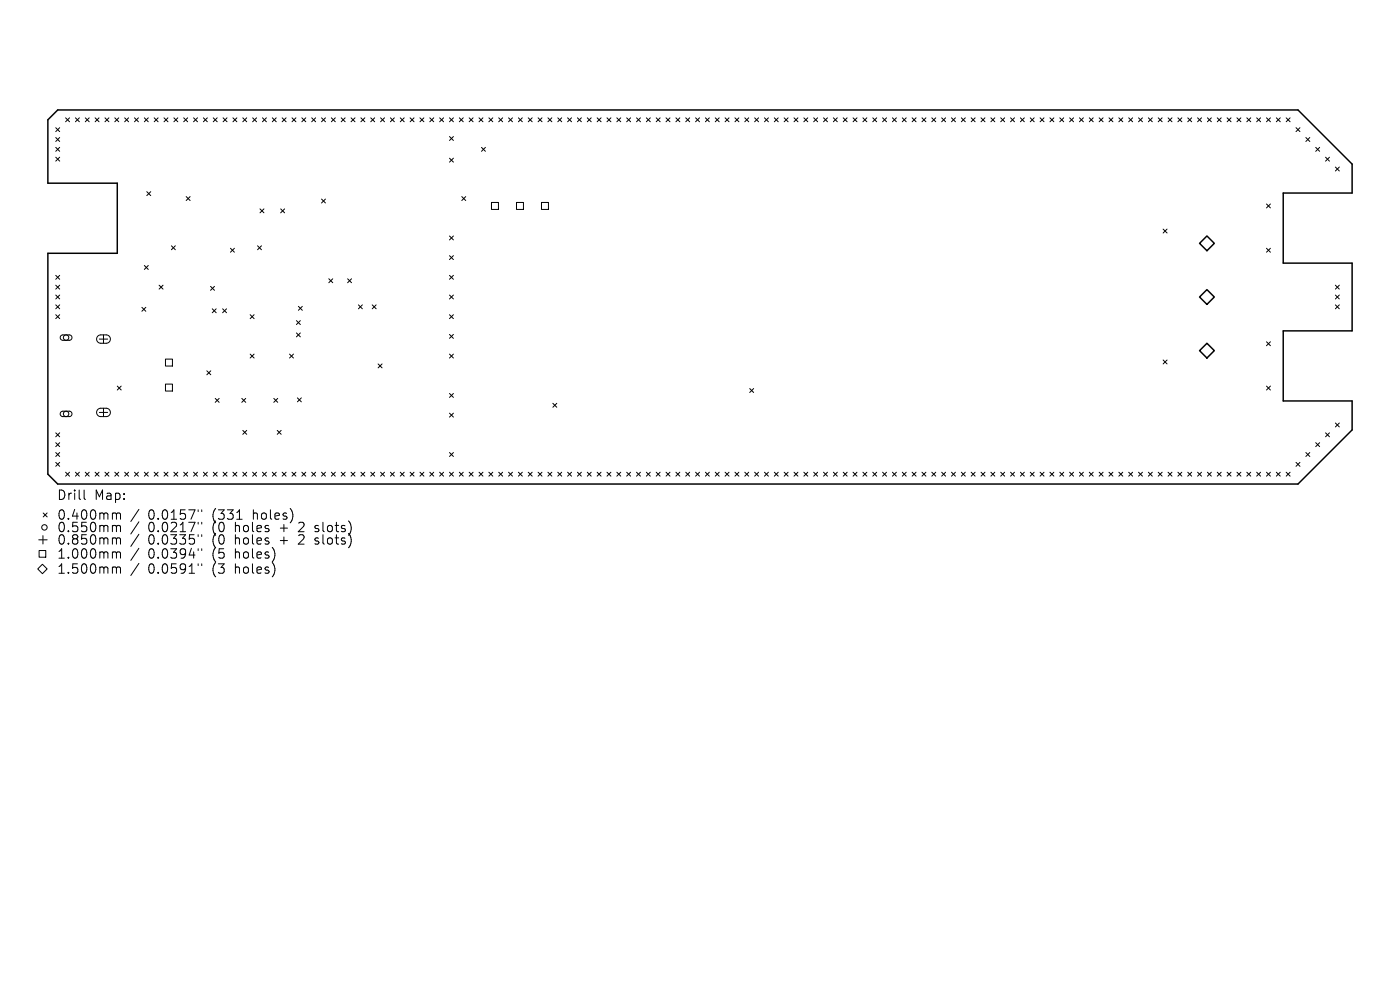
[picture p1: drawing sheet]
<svg xmlns="http://www.w3.org/2000/svg" width="297mm" height="210mm" viewBox="0 0 297 210" stroke-linecap="round" stroke-linejoin="round" font-family="sans-serif">
<defs><g id="words">
<g font-size="2.8">
<text x="12" y="106.3">Drill</text>
<text x="20" y="106.3">Map:</text>
<text x="12" y="110.5">0.400mm</text>
<text x="12" y="113.2">0.550mm</text>
<text x="31.4" y="110.5">0.0157&quot;</text>
<text x="31.4" y="113.2">0.0217&quot;</text>
<text x="45.2" y="110.5">(331</text>
<text x="45.2" y="113.2">(0</text>
<text x="50.1" y="113.2">holes</text>
<text x="53.9" y="110.5">holes)</text>
<text x="59.9" y="113.2">+</text>
<text x="64.1" y="113.2">2</text>
<text x="67.7" y="113.2">slots)</text>
<text x="12" y="115.8">0.850mm</text>
<text x="12" y="118.8">1.000mm</text>
<text x="31.4" y="115.8">0.0335&quot;</text>
<text x="31.4" y="118.8">0.0394&quot;</text>
<text x="45.2" y="115.8">(0</text>
<text x="45.2" y="118.8">(5</text>
<text x="50.1" y="115.8">holes</text>
<text x="50.1" y="118.8">holes)</text>
<text x="59.9" y="115.8">+</text>
<text x="64.1" y="115.8">2</text>
<text x="67.7" y="115.8">slots)</text>
<text x="12" y="122">1.500mm</text>
<text x="31.4" y="122">0.0591&quot;</text>
<text x="45.2" y="122">(3</text>
<text x="50.1" y="122">holes)</text>
</g>
</g></defs>
<path d="M10.2 25.4l2-2.1h263.2l11.4 11.5v6.2h-14.6v14.8h14.6v14.4h-14.6v14.9h14.6v6.1l-11.4 11.5h-263.2l-2-2.1v-46.9h14.7v-14.8h-14.7zM254.5 51.6l1.5-1.5 1.6 1.5-1.6 1.6zM254.5 63l1.5-1.6 1.6 1.6-1.6 1.6zM254.5 74.4l1.5-1.6 1.6 1.6-1.6 1.5z" fill="none" stroke="#000" stroke-width=".31"/>
<g fill="none" stroke="#000" stroke-width=".21">
<path d="M11.8 27.1l.9 .8M11.8 29.2l.9 .8M11.8 31.3l.9 .8M11.8 33.3l.9 .9M12.7 27.1l-.9 .8M12.7 29.2l-.9 .8M12.7 31.3l-.9 .8M12.7 33.3l-.9 .9M13.9 25l.9 .8M14.8 25l-.9 .8M16 25l.8 .8M16.8 25l-.8 .8"/>
<path d="M18.1 25l.8 .8M18.9 25l-.8 .8M20.2 25l.8 .8M21 25l-.8 .8M22.3 25l.8 .8M23.1 25l-.8 .8M24.4 25l.8 .8M25.2 25l-.8 .8M26.4 25l.9 .8M27.3 25l-.9 .8M28.5 25l.9 .8M29.4 25l-.9 .8"/>
<path d="M30.6 25l.9 .8M31.5 25l-.9 .8M32.7 25l.8 .8M33.5 25l-.8 .8M34.8 25l.8 .8M35.6 25l-.8 .8M36.9 25l.8 .8M37.7 25l-.8 .8M39 25l.8 .8M39.8 25l-.8 .8M41.1 25l.8 .8M41.9 25l-.8 .8"/>
<path d="M43.2 25l.8 .8M44 25l-.8 .8M45.2 25l.9 .8M46.1 25l-.9 .8M47.3 25l.9 .8M48.2 25l-.9 .8M49.4 25l.9 .8M50.3 25l-.9 .8M51.5 25l.8 .8M52.3 25l-.8 .8M53.6 25l.8 .8M54.4 25l-.8 .8"/>
<path d="M55.7 25l.8 .8M56.5 25l-.8 .8M57.8 25l.8 .8M58.6 25l-.8 .8M59.9 25l.8 .8M60.7 25l-.8 .8M61.9 25l.9 .8M62.8 25l-.9 .8M64 25l.9 .8M64.9 25l-.9 .8M66.1 25l.9 .8M67 25l-.9 .8"/>
<path d="M68.2 25l.8 .8M69 25l-.8 .8M70.3 25l.8 .8M71.1 25l-.8 .8M72.4 25l.8 .8M73.2 25l-.8 .8M74.5 25l.8 .8M75.3 25l-.8 .8M76.6 25l.8 .8M77.4 25l-.8 .8M78.7 25l.8 .8M79.5 25l-.8 .8"/>
<path d="M80.7 25l.9 .8M81.6 25l-.9 .8M82.8 25l.9 .8M83.7 25l-.9 .8M84.9 25l.9 .8M85.8 25l-.9 .8M87 25l.8 .8M87.8 25l-.8 .8M89.1 25l.8 .8M89.9 25l-.8 .8M91.2 25l.8 .8M92 25l-.8 .8"/>
<path d="M93.3 25l.8 .8M94.1 25l-.8 .8M95.4 25l.8 .8M95.4 29l.8 .8M95.4 33.6l.8 .8M96.2 25l-.8 .8M96.2 33.6l-.8 .8M96.2 29l-.8 .8M97.4 25l.9 .8M98.3 25l-.9 .8M99.5 25l.9 .8M100.4 25l-.9 .8"/>
<path d="M101.6 25l.9 .8M102.1 31.3l.9 .8M102.5 25l-.9 .8M103 31.3l-.9 .8M103.7 25l.8 .8M104.5 25l-.8 .8M105.8 25l.8 .8M106.6 25l-.8 .8M107.9 25l.8 .8M108.7 25l-.8 .8M110 25l.8 .8M110.8 25l-.8 .8"/>
<path d="M112.1 25l.8 .8M112.9 25l-.8 .8M114.1 25l.9 .8M115 25l-.9 .8M116.2 25l.9 .8M117.1 25l-.9 .8M118.3 25l.9 .8M119.2 25l-.9 .8M120.4 25l.8 .8M121.2 25l-.8 .8M122.5 25l.8 .8M123.3 25l-.8 .8"/>
<path d="M124.6 25l.8 .8M125.4 25l-.8 .8M126.7 25l.8 .8M127.5 25l-.8 .8M128.8 25l.8 .8M129.6 25l-.8 .8M130.9 25l.8 .8M131.7 25l-.8 .8M132.9 25l.9 .8M133.8 25l-.9 .8M135 25l.9 .8M135.9 25l-.9 .8"/>
<path d="M137.1 25l.9 .8M138 25l-.9 .8M139.2 25l.8 .8M140 25l-.8 .8M141.3 25l.8 .8M142.1 25l-.8 .8M143.4 25l.8 .8M144.2 25l-.8 .8M145.5 25l.8 .8M146.3 25l-.8 .8M147.6 25l.8 .8M148.4 25l-.8 .8"/>
<path d="M149.6 25l.9 .8M150.5 25l-.9 .8M151.7 25l.9 .8M152.6 25l-.9 .8M153.8 25l.9 .8M154.7 25l-.9 .8M155.9 25l.8 .8M156.7 25l-.8 .8M158 25l.8 .8M158.8 25l-.8 .8M160.1 25l.8 .8M160.9 25l-.8 .8"/>
<path d="M162.2 25l.8 .8M163 25l-.8 .8M164.3 25l.8 .8M165.1 25l-.8 .8M166.4 25l.8 .8M167.2 25l-.8 .8M168.4 25l.9 .8M169.3 25l-.9 .8M170.5 25l.9 .8M171.4 25l-.9 .8M172.6 25l.9 .8M173.5 25l-.9 .8"/>
<path d="M174.7 25l.8 .8M175.5 25l-.8 .8M176.8 25l.8 .8M177.6 25l-.8 .8M178.9 25l.8 .8M179.7 25l-.8 .8M181 25l.8 .8M181.8 25l-.8 .8M183.1 25l.8 .8M183.9 25l-.8 .8M185.1 25l.9 .8M186 25l-.9 .8"/>
<path d="M187.2 25l.9 .8M188.1 25l-.9 .8M189.3 25l.9 .8M190.2 25l-.9 .8M191.4 25l.8 .8M192.2 25l-.8 .8M193.5 25l.8 .8M194.3 25l-.8 .8M195.6 25l.8 .8M196.4 25l-.8 .8M197.7 25l.8 .8M198.5 25l-.8 .8"/>
<path d="M199.8 25l.8 .8M200.6 25l-.8 .8M201.9 25l.8 .8M202.7 25l-.8 .8M203.9 25l.9 .8M204.8 25l-.9 .8M206 25l.9 .8M206.9 25l-.9 .8M208.1 25l.9 .8M209 25l-.9 .8M210.2 25l.8 .8M211 25l-.8 .8"/>
<path d="M212.3 25l.8 .8M213.1 25l-.8 .8M214.4 25l.8 .8M215.2 25l-.8 .8M216.5 25l.8 .8M217.3 25l-.8 .8M218.6 25l.8 .8M219.4 25l-.8 .8M220.6 25l.9 .8M221.5 25l-.9 .8M222.7 25l.9 .8M223.6 25l-.9 .8"/>
<path d="M224.8 25l.9 .8M225.7 25l-.9 .8M226.9 25l.8 .8M227.7 25l-.8 .8M229 25l.8 .8M229.8 25l-.8 .8M231.1 25l.8 .8M231.9 25l-.8 .8M233.2 25l.8 .8M234 25l-.8 .8M235.3 25l.8 .8M236.1 25l-.8 .8"/>
<path d="M237.4 25l.8 .8M238.2 25l-.8 .8M239.4 25l.9 .8M240.3 25l-.9 .8M241.5 25l.9 .8M242.4 25l-.9 .8M243.6 25l.9 .8M244.5 25l-.9 .8M245.7 25l.8 .8M246.5 25l-.8 .8M247.8 25l.8 .8M248.6 25l-.8 .8"/>
<path d="M249.9 25l.8 .8M250.7 25l-.8 .8M252 25l.8 .8M252.8 25l-.8 .8M254.1 25l.8 .8M254.9 25l-.8 .8M256.1 25l.9 .8M257 25l-.9 .8M258.2 25l.9 .8M259.1 25l-.9 .8M260.3 25l.9 .8M261.2 25l-.9 .8"/>
<path d="M262.4 25l.8 .8M263.2 25l-.8 .8M264.5 25l.8 .8M265.3 25l-.8 .8M266.6 25l.8 .8M267.4 25l-.8 .8M268.7 25l.8 .8M269.5 25l-.8 .8M270.8 25l.8 .8M271.6 25l-.8 .8M272.9 25l.8 .8M273.7 25l-.8 .8"/>
<path d="M274.9 27.1l.9 .8M275.8 27.1l-.9 .8M277 29.2l.9 .8M277.9 29.2l-.9 .8M279.1 31.3l.9 .8M280 31.3l-.9 .8M281.2 33.3l.8 .9M282 33.3l-.8 .9M283.3 35.4l.8 .9M284.1 35.4l-.8 .9M11.8 58.4l.9 .8M12.7 58.4l-.9 .8"/>
<path d="M30.6 56.3l.9 .9M31.1 40.7l.9 .8M31.5 56.3l-.9 .9M32 40.7l-.9 .8M36.4 52.1l.8 .9M37.2 52.1l-.8 .9M39.5 41.7l.8 .8M40.3 41.7l-.8 .8M48.9 52.7l.8 .8M49.7 52.7l-.8 .8M54.6 52.1l.9 .9M55.2 44.3l.8 .8"/>
<path d="M55.5 52.1l-.9 .9M56 44.3l-.8 .8M59.5 44.3l.9 .8M60.4 44.3l-.9 .8M68.2 42.2l.8 .9M69 42.2l-.8 .9M69.8 59.1l.8 .9M70.6 59.1l-.8 .9M73.7 59.1l.9 .9M74.6 59.1l-.9 .9M95.4 50.1l.8 .8M95.4 54.2l.8 .9"/>
<path d="M95.4 58.4l.8 .8M96.2 50.1l-.8 .8M96.2 58.4l-.8 .8M96.2 54.2l-.8 .9M98 41.7l.8 .8M98.8 41.7l-.8 .8M104.3 42.9h1.4v1.5h-1.4zM109.6 42.9h1.4v1.5h-1.4zM114.9 42.9h1.4v1.5h-1.4zM246.8 48.6l.8 .8M247.6 48.6l-.8 .8M268.7 43.3l.8 .8"/>
<path d="M268.7 52.7l.8 .8M269.5 43.3l-.8 .8M269.5 52.7l-.8 .8M11.8 60.5l.9 .8M11.8 62.6l.9 .8M11.8 64.7l.9 .8M11.8 66.8l.9 .8M12.7 60.5l-.9 .8M12.7 62.6l-.9 .8M12.7 64.7l-.9 .8M12.7 66.8l-.9 .8M12.9 71.2l.4-.2 1.5 .1 .4 .2 .1 .5-.5 .4h-1.6l-.4-.4z"/>
<path d="M20.8 71.3l.4-.2 1.3-.1a.89 .89 0 0 1 .9 .9 .89 .89 0 0 1-.9 .9h-1.1a.89 .89 0 0 1-.8-.5 .89 .89 0 0 1 .2-1zM21.1 71.9h1.7M22 71v1.8M30.1 65.2l.8 .8M30.9 65.2l-.8 .8M33.8 60.5l.8 .8M34.6 60.5l-.8 .8M35.1 76.2h1.5v1.4h-1.5zM43.9 78.7l.8 .8M44.7 60.7l.8 .9M44.7 78.7l-.8 .8M45 65.5l.9 .8"/>
<path d="M45.5 60.7l-.8 .9M45.9 65.5l-.9 .8M47.2 65.5l.9 .8M48.1 65.5l-.9 .8M53.1 66.8l.8 .8M53.1 75.1l.8 .8M53.9 66.8l-.8 .8M53.9 75.1l-.8 .8M61.4 75.1l.9 .8M62.3 75.1l-.9 .8M62.9 68l.8 .8M62.9 70.6l.8 .9"/>
<path d="M63.3 65l.8 .8M63.7 68l-.8 .8M63.7 70.6l-.8 .9M64.1 65l-.8 .8M76 64.7l.9 .8M76.9 64.7l-.9 .8M79 64.7l.8 .8M79.8 64.7l-.8 .8M80.2 77.2l.9 .8M81.1 77.2l-.9 .8M95.4 62.6l.8 .8M95.4 66.8l.8 .8"/>
<path d="M95.4 70.9l.8 .9M95.4 75.1l.8 .8M96.2 62.6l-.8 .8M96.2 70.9l-.8 .9M96.2 75.1l-.8 .8M96.2 66.8l-.8 .8M246.8 76.4l.8 .8M247.6 76.4l-.8 .8M268.7 72.5l.8 .8M269.5 72.5l-.8 .8M283.3 60.5l.8 .8M283.3 62.6l.8 .8"/>
<path d="M283.3 64.7l.8 .8M284.1 60.5l-.8 .8M284.1 62.6l-.8 .8M284.1 64.7l-.8 .8M11.8 91.8l.9 .9M11.8 93.9l.9 .8M11.8 96l.9 .8M11.8 98.1l.9 .8M12.7 91.8l-.9 .9M12.7 93.9l-.9 .8M12.7 96l-.9 .8M12.7 98.1l-.9 .8"/>
<path d="M12.9 87.4l.4-.2h1.5l.4 .3 .1 .4-.5 .5h-1.6l-.4-.5zM20.8 86.9l.4-.3h1.3a.89 .89 0 0 1 .9 .9 .89 .89 0 0 1-.9 .9h-1.1a.89 .89 0 0 1-.8-.6 .89 .89 0 0 1 .2-.9zM21.1 87.5h1.7M22 86.6v1.8M24.9 81.9l.8 .8M25.7 81.9l-.8 .8M35.1 81.5h1.5v1.5h-1.5zM45.7 84.5l.8 .8M46.5 84.5l-.8 .8M51.3 84.5l.8 .8M51.5 91.3l.8 .8M52.1 84.5l-.8 .8"/>
<path d="M52.3 91.3l-.8 .8M58.1 84.5l.8 .8M58.8 91.3l.8 .8M58.9 84.5l-.8 .8M59.6 91.3l-.8 .8M63.1 84.4l.8 .8M63.9 84.4l-.8 .8M95.4 83.5l.8 .8M95.4 87.6l.8 .9M95.4 96l.8 .8M96.2 83.5l-.8 .8M96.2 87.6l-.8 .9"/>
<path d="M96.2 96l-.8 .8M117.3 85.6l.8 .8M118.1 85.6l-.8 .8M159 82.4l.9 .9M159.9 82.4l-.9 .9M268.7 81.9l.8 .8M269.5 81.9l-.8 .8M274.9 98.1l.9 .8M275.8 98.1l-.9 .8M277 96l.9 .8M277.9 96l-.9 .8M279.1 93.9l.9 .8"/>
<path d="M280 93.9l-.9 .8M281.2 91.8l.8 .9M282 91.8l-.8 .9M283.3 89.7l.8 .9M284.1 89.7l-.8 .9M8.2 114.5h1.8M8.3 116.8h1.4v1.4h-1.4zM9.1 113.6v1.8M9.2 108.8l.8 .9M10 108.8l-.8 .9M13.9 100.2l.9 .8M14.8 100.2l-.9 .8"/>
<path d="M16 100.2l.8 .8M16.8 100.2l-.8 .8M17.8 103.9v1.8l.3 .2M18.1 100.2l.8 .8M18.9 100.2l-.8 .8M20.2 100.2l.8 .8M21 100.2l-.8 .8M22.3 100.2l.8 .8M23.1 100.2l-.8 .8M24.1 108.8h.3l.3 .3M24.1 111.5h.3l.3 .2M24.1 114.1h.3l.3 .3"/>
<path d="M24.1 117.1h.3l.3 .3M24.4 100.2l.8 .8M24.7 109.1l.3-.3 .5 .1 .1 1.2M24.7 109.1v1M24.7 111.7v1.1M24.7 114.4v1M24.7 117.4v1M24.7 111.7l.3-.2 .5 .1 .1 1.2M24.7 114.4l.3-.3 .5 .1 .1 1.2M24.7 117.4l.3-.3 .5 .1 .1 1.2M25.2 100.2l-.8 .8M26.4 100.2l.9 .8"/>
<path d="M27.3 100.2l-.9 .8M28.5 100.2l.9 .8M29.4 100.2l-.9 .8M29.5 108.1l-1.7 2.5M29.5 110.7l-1.7 2.6M29.5 113.3l-1.7 2.6M29.5 116.3l-1.7 2.6M29.5 119.5l-1.7 2.6M30.6 100.2l.9 .8M31.5 100.2l-.9 .8M32.7 100.2l.8 .8M33.5 100.2l-.8 .8"/>
<path d="M34.8 100.2l.8 .8M35.6 100.2l-.8 .8M36.9 100.2l.8 .8M37.7 100.2l-.8 .8M39 100.2l.8 .8M39.8 100.2l-.8 .8M41.1 100.2l.8 .8M41.9 100.2l-.8 .8M42 108.1v.4M42 110.8v.4M42 113.4v.4M42 116.4v.4"/>
<path d="M42 119.6v.4M42.8 108.1v.4M42.8 110.8v.4M42.8 113.4v.4M42.8 116.4v.4M42.8 119.6v.4M43.2 100.2l.8 .8M44 100.2l-.8 .8M45.2 100.2l.9 .8M46.1 100.2l-.9 .8M47.3 100.2l.9 .8M48.2 100.2l-.9 .8"/>
<path d="M49.4 100.2l.9 .8M50.2 110.1h1.2M50.3 100.2l-.9 .8M51.5 100.2l.8 .8M52.3 100.2l-.8 .8M53.6 100.2l.8 .8M54.4 100.2l-.8 .8M55.7 100.2l.8 .8M56.5 100.2l-.8 .8M57.8 100.2l.8 .8M58.6 100.2l-.8 .8M59.9 100.2l.8 .8"/>
<path d="M60.7 100.2l-.8 .8M61.9 100.2l.9 .8M62.8 100.2l-.9 .8M64 100.2l.9 .8M64.9 100.2l-.9 .8M66.1 100.2l.9 .8M66.8 112.7l.2 .1M66.8 115.3l.2 .1M66.9 111.6v.4M66.9 114.2v.5M67 100.2l-.9 .8M68.2 100.2l.8 .8"/>
<path d="M69 100.2l-.8 .8M70.3 100.2l.8 .8M71.1 100.2l-.8 .8M72.4 100.2l.8 .8M73.2 100.2l-.8 .8M74.5 100.2l.8 .8M75.3 100.2l-.8 .8M76.6 100.2l.8 .8M77.4 100.2l-.8 .8M78.7 100.2l.8 .8M79.5 100.2l-.8 .8M80.7 100.2l.9 .8"/>
<path d="M81.6 100.2l-.9 .8M82.8 100.2l.9 .8M83.7 100.2l-.9 .8M84.9 100.2l.9 .8M85.8 100.2l-.9 .8M87 100.2l.8 .8M87.8 100.2l-.8 .8M89.1 100.2l.8 .8M89.9 100.2l-.8 .8M91.2 100.2l.8 .8M92 100.2l-.8 .8M93.3 100.2l.8 .8"/>
<path d="M94.1 100.2l-.8 .8M95.4 100.2l.8 .8M96.2 100.2l-.8 .8M97.4 100.2l.9 .8M98.3 100.2l-.9 .8M99.5 100.2l.9 .8M100.4 100.2l-.9 .8M101.6 100.2l.9 .8M102.5 100.2l-.9 .8M103.7 100.2l.8 .8M104.5 100.2l-.8 .8M105.8 100.2l.8 .8"/>
<path d="M106.6 100.2l-.8 .8M107.9 100.2l.8 .8M108.7 100.2l-.8 .8M110 100.2l.8 .8M110.8 100.2l-.8 .8M112.1 100.2l.8 .8M112.9 100.2l-.8 .8M114.1 100.2l.9 .8M115 100.2l-.9 .8M116.2 100.2l.9 .8M117.1 100.2l-.9 .8M118.3 100.2l.9 .8"/>
<path d="M119.2 100.2l-.9 .8M120.4 100.2l.8 .8M121.2 100.2l-.8 .8M122.5 100.2l.8 .8M123.3 100.2l-.8 .8M124.6 100.2l.8 .8M125.4 100.2l-.8 .8M126.7 100.2l.8 .8M127.5 100.2l-.8 .8M128.8 100.2l.8 .8M129.6 100.2l-.8 .8M130.9 100.2l.8 .8"/>
<path d="M131.7 100.2l-.8 .8M132.9 100.2l.9 .8M133.8 100.2l-.9 .8M135 100.2l.9 .8M135.9 100.2l-.9 .8M137.1 100.2l.9 .8M138 100.2l-.9 .8M139.2 100.2l.8 .8M140 100.2l-.8 .8M141.3 100.2l.8 .8M142.1 100.2l-.8 .8M143.4 100.2l.8 .8"/>
<path d="M144.2 100.2l-.8 .8M145.5 100.2l.8 .8M146.3 100.2l-.8 .8M147.6 100.2l.8 .8M148.4 100.2l-.8 .8M149.6 100.2l.9 .8M150.5 100.2l-.9 .8M151.7 100.2l.9 .8M152.6 100.2l-.9 .8M153.8 100.2l.9 .8M154.7 100.2l-.9 .8M155.9 100.2l.8 .8"/>
<path d="M156.7 100.2l-.8 .8M158 100.2l.8 .8M158.8 100.2l-.8 .8M160.1 100.2l.8 .8M160.9 100.2l-.8 .8M162.2 100.2l.8 .8M163 100.2l-.8 .8M164.3 100.2l.8 .8M165.1 100.2l-.8 .8M166.4 100.2l.8 .8M167.2 100.2l-.8 .8M168.4 100.2l.9 .8"/>
<path d="M169.3 100.2l-.9 .8M170.5 100.2l.9 .8M171.4 100.2l-.9 .8M172.6 100.2l.9 .8M173.5 100.2l-.9 .8M174.7 100.2l.8 .8M175.5 100.2l-.8 .8M176.8 100.2l.8 .8M177.6 100.2l-.8 .8M178.9 100.2l.8 .8M179.7 100.2l-.8 .8M181 100.2l.8 .8"/>
<path d="M181.8 100.2l-.8 .8M183.1 100.2l.8 .8M183.9 100.2l-.8 .8M185.1 100.2l.9 .8M186 100.2l-.9 .8M187.2 100.2l.9 .8M188.1 100.2l-.9 .8M189.3 100.2l.9 .8M190.2 100.2l-.9 .8M191.4 100.2l.8 .8M192.2 100.2l-.8 .8M193.5 100.2l.8 .8"/>
<path d="M194.3 100.2l-.8 .8M195.6 100.2l.8 .8M196.4 100.2l-.8 .8M197.7 100.2l.8 .8M198.5 100.2l-.8 .8M199.8 100.2l.8 .8M200.6 100.2l-.8 .8M201.9 100.2l.8 .8M202.7 100.2l-.8 .8M203.9 100.2l.9 .8M204.8 100.2l-.9 .8M206 100.2l.9 .8"/>
<path d="M206.9 100.2l-.9 .8M208.1 100.2l.9 .8M209 100.2l-.9 .8M210.2 100.2l.8 .8M211 100.2l-.8 .8M212.3 100.2l.8 .8M213.1 100.2l-.8 .8M214.4 100.2l.8 .8M215.2 100.2l-.8 .8M216.5 100.2l.8 .8M217.3 100.2l-.8 .8M218.6 100.2l.8 .8"/>
<path d="M219.4 100.2l-.8 .8M220.6 100.2l.9 .8M221.5 100.2l-.9 .8M222.7 100.2l.9 .8M223.6 100.2l-.9 .8M224.8 100.2l.9 .8M225.7 100.2l-.9 .8M226.9 100.2l.8 .8M227.7 100.2l-.8 .8M229 100.2l.8 .8M229.8 100.2l-.8 .8M231.1 100.2l.8 .8"/>
<path d="M231.9 100.2l-.8 .8M233.2 100.2l.8 .8M234 100.2l-.8 .8M235.3 100.2l.8 .8M236.1 100.2l-.8 .8M237.4 100.2l.8 .8M238.2 100.2l-.8 .8M239.4 100.2l.9 .8M240.3 100.2l-.9 .8M241.5 100.2l.9 .8M242.4 100.2l-.9 .8M243.6 100.2l.9 .8"/>
<path d="M244.5 100.2l-.9 .8M245.7 100.2l.8 .8M246.5 100.2l-.8 .8M247.8 100.2l.8 .8M248.6 100.2l-.8 .8M249.9 100.2l.8 .8M250.7 100.2l-.8 .8M252 100.2l.8 .8M252.8 100.2l-.8 .8M254.1 100.2l.8 .8M254.9 100.2l-.8 .8M256.1 100.2l.9 .8"/>
<path d="M257 100.2l-.9 .8M258.2 100.2l.9 .8M259.1 100.2l-.9 .8M260.3 100.2l.9 .8M261.2 100.2l-.9 .8M262.4 100.2l.8 .8M263.2 100.2l-.8 .8M264.5 100.2l.8 .8M265.3 100.2l-.8 .8M266.6 100.2l.8 .8M267.4 100.2l-.8 .8M268.7 100.2l.8 .8"/>
<path d="M269.5 100.2l-.8 .8M270.8 100.2l.8 .8M271.6 100.2l-.8 .8M272.9 100.2l.8 .8M273.7 100.2l-.8 .8M8 120.7l1-1 1 1-1 1zM24.1 120.3h.3l.3 .3M24.7 120.6v1M24.7 120.6l.3-.3 .5 .1 .1 1.2"/>
<circle cx="14" cy="71.6" r=".57"/>
<circle cx="14" cy="87.8" r=".57"/>
<circle cx="9.4" cy="111.9" r=".57"/>
</g>
<use href="#words"/>
</svg>
